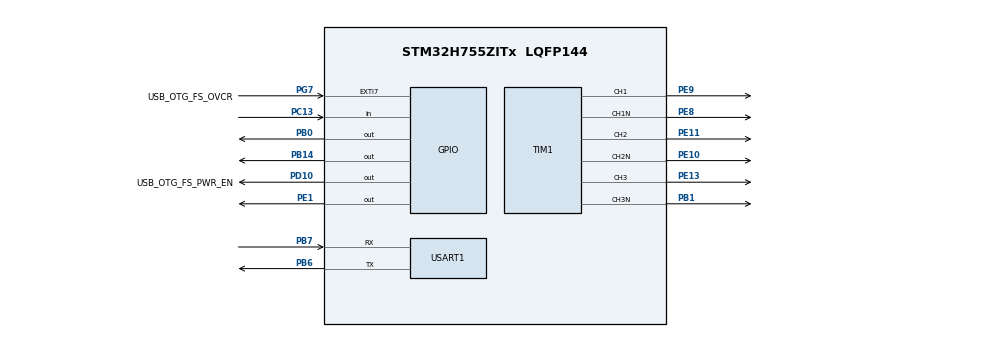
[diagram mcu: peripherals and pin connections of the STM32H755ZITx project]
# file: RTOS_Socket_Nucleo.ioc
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CortexM4.IPs=FATFS_M4\:I,FREERTOS_M4\:I,IWDG2\:I,RCC,WWDG2\:I,DMA,BDMA,MDMA,NVIC2\:I,ETH,USART3,DEBUG,PDM2PCM_M4\:I,PWR,RESMGR_UTILITY,SYS_M4\:I,USB_DEVICE_M4\:I,USB_HOST_M4\:I,CORTEX_M4\:I,GPIO,OPENAMP_M4\:I,VREFBUF,NUCLEO-H755ZI-Q
CortexM7.IPs=FATFS_M7\:I,FREERTOS_M7\:I,IWDG1\:I,RCC\:I,WWDG1\:I,DMA\:I,BDMA\:I,MDMA\:I,NVIC1\:I,ETH\:I,USART3\:I,USB_OTG_FS\:I,SYS\:I,CORTEX_M7\:I,DEBUG\:I,PDM2PCM_M7\:I,PWR\:I,RESMGR_UTILITY\:I,USB_DEVICE_M7\:I,USB_HOST_M7\:I,GPIO\:I,OPENAMP_M7\:I,VREFBUF\:I,NUCLEO-H755ZI-Q\:I,TIM1\:I,USART1\:I,TIM6\:I
Dma.Request0=USART1_TX
Dma.Request1=USART1_RX
Dma.USART1_RX.1.Direction=DMA_PERIPH_TO_MEMORY
Dma.USART1_RX.1.EventEnable=DISABLE
Dma.USART1_RX.1.FIFOMode=DMA_FIFOMODE_DISABLE
Dma.USART1_RX.1.Instance=DMA1_Stream1
Dma.USART1_RX.1.MemDataAlignment=DMA_MDATAALIGN_BYTE
Dma.USART1_RX.1.MemInc=DMA_MINC_ENABLE
Dma.USART1_RX.1.Mode=DMA_CIRCULAR
Dma.USART1_RX.1.PeriphDataAlignment=DMA_PDATAALIGN_BYTE
Dma.USART1_RX.1.PeriphInc=DMA_PINC_DISABLE
Dma.USART1_RX.1.Polarity=HAL_DMAMUX_REQ_GEN_RISING
Dma.USART1_RX.1.Priority=DMA_PRIORITY_LOW
Dma.USART1_RX.1.RequestNumber=1
Dma.USART1_RX.1.SignalID=NONE
Dma.USART1_RX.1.SyncEnable=DISABLE
Dma.USART1_RX.1.SyncPolarity=HAL_DMAMUX_SYNC_NO_EVENT
Dma.USART1_RX.1.SyncRequestNumber=1
Dma.USART1_RX.1.SyncSignalID=NONE
Dma.USART1_TX.0.Direction=DMA_MEMORY_TO_PERIPH
Dma.USART1_TX.0.EventEnable=DISABLE
Dma.USART1_TX.0.FIFOMode=DMA_FIFOMODE_DISABLE
Dma.USART1_TX.0.Instance=DMA1_Stream0
Dma.USART1_TX.0.MemDataAlignment=DMA_MDATAALIGN_BYTE
Dma.USART1_TX.0.MemInc=DMA_MINC_ENABLE
Dma.USART1_TX.0.Mode=DMA_NORMAL
Dma.USART1_TX.0.PeriphDataAlignment=DMA_PDATAALIGN_BYTE
Dma.USART1_TX.0.PeriphInc=DMA_PINC_DISABLE
Dma.USART1_TX.0.Polarity=HAL_DMAMUX_REQ_GEN_RISING
Dma.USART1_TX.0.Priority=DMA_PRIORITY_LOW
Dma.USART1_TX.0.RequestNumber=1
Dma.USART1_TX.0.SignalID=NONE
Dma.USART1_TX.0.SyncEnable=DISABLE
Dma.USART1_TX.0.SyncPolarity=HAL_DMAMUX_SYNC_NO_EVENT
Dma.USART1_TX.0.SyncRequestNumber=1
Dma.USART1_TX.0.SyncSignalID=NONE
FREERTOS_M7.Mutexes01=sl_send_lock,Dynamic,NULL,Available;dl_send_lock,Dynamic,NULL,Available;ph_send_lock,Dynamic,NULL,Available
FREERTOS_M7.Tasks01=defaultTask,24,128,StartDefaultTask,Default,NULL,Dynamic,NULL,NULL;sendTask,8,128,StartSendTask,Default,NULL,Dynamic,NULL,NULL;receiveTask,8,128,StartReceiveTask,Default,NULL,Dynamic,NULL,NULL
FREERTOS_M7.configUSE_NEWLIB_REENTRANT=1
Mcu.Family=STM32H7
Mcu.Name=STM32H755ZITx
Mcu.Package=LQFP144
NUCLEO-H755ZI-Q.BUTTON=1
NUCLEO-H755ZI-Q.LD1=true
NUCLEO-H755ZI-Q.LD2=true
NUCLEO-H755ZI-Q.LD3=true
NUCLEO-H755ZI-Q.VCP=true
NVIC1.DMA1_Stream0_IRQn=true\:5\:0\:false\:false\:true\:true\:false\:true\:true
NVIC1.DMA1_Stream1_IRQn=true\:5\:0\:false\:false\:true\:true\:false\:true\:true
NVIC1.EXTI15_10_IRQn=true\:5\:0\:false\:false\:true\:true\:false\:true\:true
NVIC1.PriorityGroup=NVIC_PRIORITYGROUP_4
NVIC1.TIM6_DAC_IRQn=true\:15\:0\:false\:false\:true\:false\:false\:true\:true
NVIC1.TimeBase=TIM6_DAC_IRQn
NVIC1.TimeBaseIP=TIM6
NVIC2.PriorityGroup=NVIC_PRIORITYGROUP_4
PA1.PinAttribute=CortexM7
PA1.Signal=ETH_REF_CLK
PA11.PinAttribute=CortexM7
PA11.Signal=USB_OTG_FS_DM
PA12.PinAttribute=CortexM7
PA12.Signal=USB_OTG_FS_DP
PA2.PinAttribute=CortexM7
PA2.Signal=ETH_MDIO
PA7.PinAttribute=CortexM7
PA7.Signal=ETH_CRS_DV
PA8.PinAttribute=CortexM7
PA8.Signal=USB_OTG_FS_SOF
PA9.PinAttribute=CortexM7
PA9.Signal=USB_OTG_FS_VBUS
PB0.Signal=GPIO_Output
PB1.Mode=PWM Generation3 CH3 CH3N
PB1.PinAttribute=CortexM7
PB1.Signal=TIM1_CH3N
PB13.PinAttribute=CortexM7
PB13.Signal=ETH_TXD1
PB14.Signal=GPIO_Output
PB6.Mode=Asynchronous
PB6.PinAttribute=CortexM7
PB6.Signal=USART1_TX
PB7.Mode=Asynchronous
PB7.PinAttribute=CortexM7
PB7.Signal=USART1_RX
PC1.PinAttribute=CortexM7
PC1.Signal=ETH_MDC
PC13.Signal=GPIO_Input
PC14-OSC32_IN\ (OSC32_IN).PinAttribute=Free
PC14-OSC32_IN\ (OSC32_IN).Signal=RCC_OSC32_IN
PC15-OSC32_OUT\ (OSC32_OUT).PinAttribute=Free
PC15-OSC32_OUT\ (OSC32_OUT).Signal=RCC_OSC32_OUT
PC4.PinAttribute=CortexM7
PC4.Signal=ETH_RXD0
PC5.PinAttribute=CortexM7
PC5.Signal=ETH_RXD1
PD10.GPIO_Label=USB_OTG_FS_PWR_EN
PD10.PinAttribute=Free
PD10.Signal=GPIO_Output
PD8.Signal=USART3_TX
PD9.Signal=USART3_RX
PE1.Signal=GPIO_Output
PE10.Mode=PWM Generation2 CH2 CH2N
PE10.PinAttribute=CortexM7
PE10.Signal=TIM1_CH2N
PE11.PinAttribute=CortexM7
PE11.Signal=S_TIM1_CH2
PE13.PinAttribute=CortexM7
PE13.Signal=S_TIM1_CH3
PE8.Mode=PWM Generation1 CH1 CH1N
PE8.PinAttribute=CortexM7
PE8.Signal=TIM1_CH1N
PE9.PinAttribute=CortexM7
PE9.Signal=S_TIM1_CH1
PG11.PinAttribute=CortexM7
PG11.Signal=ETH_TX_EN
PG13.PinAttribute=CortexM7
PG13.Signal=ETH_TXD0
PG7.GPIO_Label=USB_OTG_FS_OVCR
PG7.PinAttribute=Free
PG7.Signal=GPXTI7
PH0-OSC_IN\ (PH0).PinAttribute=Free
PH0-OSC_IN\ (PH0).Signal=RCC_OSC_IN
PH1-OSC_OUT\ (PH1).PinAttribute=Free
PH1-OSC_OUT\ (PH1).Signal=RCC_OSC_OUT
ProjectManager.HeapSize=M4-0x200,M7-0x200
ProjectManager.StackSize=M4-0x400,M7-0x400
ProjectManager.TargetToolchain=STM32CubeIDE
RCC.ADCFreq_Value=129000000
RCC.APB1Freq_Value=120000000
RCC.APB2Freq_Value=120000000
RCC.APB3Freq_Value=120000000
RCC.APB4Freq_Value=120000000
RCC.CortexFreq_Value=480000000
RCC.D1PPRE=RCC_APB3_DIV2
RCC.D2PPRE1=RCC_APB1_DIV2
RCC.D2PPRE2=RCC_APB2_DIV2
RCC.D3PPRE=RCC_APB4_DIV2
RCC.DIVM1=4
RCC.DIVN1=60
RCC.DIVQ1=5
RCC.HCLKFreq_Value=240000000
RCC.HPRE=RCC_HCLK_DIV2
RCC.PLL2FRACN=0
RCC.PLL3FRACN=0
RCC.PLLFRACN=0
RCC.SYSCLKFreq_VALUE=480000000
RCC.SYSCLKSource=RCC_SYSCLKSOURCE_PLLCLK
RCC.SupplySource=PWR_LDO_SUPPLY
RCC.USBFreq_Value=192000000
SH.S_TIM1_CH1.0=TIM1_CH1,PWM Generation1 CH1 CH1N
SH.S_TIM1_CH2.0=TIM1_CH2,PWM Generation2 CH2 CH2N
SH.S_TIM1_CH3.0=TIM1_CH3,PWM Generation3 CH3 CH3N
TIM1.Channel-PWM\ Generation1\ CH1\ CH1N=TIM_CHANNEL_1
TIM1.Channel-PWM\ Generation2\ CH2\ CH2N=TIM_CHANNEL_2
TIM1.Channel-PWM\ Generation3\ CH3\ CH3N=TIM_CHANNEL_3
USART1.VirtualMode-Asynchronous=VM_ASYNC
VP_FREERTOS_M7_VS_CMSIS_V2.Mode=CMSIS_V2
VP_NUCLEO-H755ZI-Q_VS_BSP_COMMON.Mode=COMMON
VP_SYS_M4_VS_Systick.Mode=SysTick
VP_SYS_VS_tim6.Mode=TIM6
board=NUCLEO-H755ZI-Q

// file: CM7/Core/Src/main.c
/* USER CODE BEGIN Header */
/**
  ******************************************************************************
  * @file           : main.c
  * @brief          : Main program body
  ******************************************************************************
  * @attention
  *
  * Copyright (c) 2024 STMicroelectronics.
  * All rights reserved.
  *
  * This software is licensed under terms that can be found in the LICENSE file
  * in the root directory of this software component.
  * If no LICENSE file comes with this software, it is provided AS-IS.
  *
  ******************************************************************************
  */
/* USER CODE END Header */
#include "main.h"
#include "cmsis_os.h"

/* USER CODE BEGIN Includes */
#include <string.h>
#include <string.h>
#include <stdlib.h>
#include <stdio.h>

/* USER CODE END Includes */

/* USER CODE BEGIN PD */

#ifndef HSEM_ID_0
#define HSEM_ID_0 (0U) /* HW semaphore 0*/
#endif

#define RX_BUFFER_SIZE 256
#define UART_TIMEOUT 100
#define PACKET_MIN_LENGTH 6
#define SERVER_IP "13.233.25.158"
#define SERVER_PORT 3000
#define SOCKET_INDEX 0

/* USER CODE END PD */

TIM_HandleTypeDef htim1;

UART_HandleTypeDef huart1;
DMA_HandleTypeDef hdma_usart1_rx;
DMA_HandleTypeDef hdma_usart1_tx;

/* Definitions for defaultTask */
osThreadId_t defaultTaskHandle;
const osThreadAttr_t defaultTask_attributes = {
  .name = "defaultTask",
  .stack_size = 128 * 4,
  .priority = (osPriority_t) osPriorityNormal,
};
/* Definitions for sendTask */
osThreadId_t sendTaskHandle;
const osThreadAttr_t sendTask_attributes = {
  .name = "sendTask",
  .stack_size = 128 * 4,
  .priority = (osPriority_t) osPriorityLow,
};
/* Definitions for receiveTask */
osThreadId_t receiveTaskHandle;
const osThreadAttr_t receiveTask_attributes = {
  .name = "receiveTask",
  .stack_size = 128 * 4,
  .priority = (osPriority_t) osPriorityLow,
};
/* Definitions for gpsTask */
osThreadId_t gpsTaskHandle;
const osThreadAttr_t gpsTask_attributes = {
  .name = "gpsTask",
  .stack_size = 128 * 4,
  .priority = (osPriority_t) osPriorityLow,
};
/* Definitions for sl_send_lock */
osMutexId_t sl_send_lockHandle;
const osMutexAttr_t sl_send_lock_attributes = {
  .name = "sl_send_lock"
};
/* Definitions for dl_send_lock */
osMutexId_t dl_send_lockHandle;
const osMutexAttr_t dl_send_lock_attributes = {
  .name = "dl_send_lock"
};
/* Definitions for ph_send_lock */
osMutexId_t ph_send_lockHandle;
const osMutexAttr_t ph_send_lock_attributes = {
  .name = "ph_send_lock"
};
/* Definitions for uart_lock */
osMutexId_t uart_lockHandle;
const osMutexAttr_t uart_lock_attributes = {
  .name = "uart_lock"
};
/* USER CODE BEGIN PV */
char txBuffer[RX_BUFFER_SIZE];        // Buffer for sending AT commands
char rxBuffer[RX_BUFFER_SIZE];        // Buffer for receiving AT responses
char checkBuffer[RX_BUFFER_SIZE];

uint16_t writeIndex = 0;  // Updated by DMA
uint16_t readIndex = 0;   // Updated by application
uint8_t propertyIndex = 0;

typedef enum {
    IMMOBILIZE_STATUS = 0x01,
    RPM_PRESET        = 0x02,
    GPS               = 0x03,
    CURRENT           = 0x04,
    VOLTAGE           = 0x05,
    RPM               = 0x06,
    TEMPERATURE       = 0x07,
    NETWORK_STRENGTH  = 0x08
} ServerPropertyType;

typedef struct {
    uint8_t immobilizeStatus[1]; // 1 byte
    uint8_t rpmPreset[1];        // 1 byte
    uint8_t gpsData[32];          // 6 bytes
    uint8_t currentData[2];      // 2 bytes
    uint8_t voltageData[2];      // 2 bytes
    uint8_t rpm[1];              // 1 byte
    uint8_t temperature[1];      // 1 byte
    uint8_t networkStrength[1];  // 1 byte
} serverProperties;

serverProperties serverAttributes;
/* USER CODE END PV */

void SystemClock_Config(void);
static void MX_GPIO_Init(void);
static void MX_DMA_Init(void);
static void MX_USART1_UART_Init(void);
static void MX_TIM1_Init(void);
void StartDefaultTask(void *argument);
void StartSendTask(void *argument);
void StartReceiveTask(void *argument);
void StartGpsTask(void *argument);

/* USER CODE BEGIN PFP */
void NetworkInit();
void OpenSocket();
void SocketSendData(void);
void SocketReceiveData(void);
void HandleReceivedData(uint8_t writeIndex);
uint8_t encodeServerData(ServerPropertyType type, uint8_t *packet);
void decodeServerData(uint8_t *packet, uint8_t length);
void gps(void);
/* USER CODE END PFP */

int main(void)
{

/* USER CODE BEGIN Boot_Mode_Sequence_0 */
  int32_t timeout;
/* USER CODE END Boot_Mode_Sequence_0 */

/* USER CODE BEGIN Boot_Mode_Sequence_1 */
  /* Wait until CPU2 boots and enters in stop mode or timeout*/
  timeout = 0xFFFF;
  while((__HAL_RCC_GET_FLAG(RCC_FLAG_D2CKRDY) != RESET) && (timeout-- > 0));
  if ( timeout < 0 )
  {
  Error_Handler();
  }
/* USER CODE END Boot_Mode_Sequence_1 */
  /* MCU Configuration--------------------------------------------------------*/

  /* Reset of all peripherals, Initializes the Flash interface and the Systick. */
  HAL_Init();

  /* Configure the system clock */
  SystemClock_Config();
/* USER CODE BEGIN Boot_Mode_Sequence_2 */
/* When system initialization is finished, Cortex-M7 will release Cortex-M4 by means of
HSEM notification */
/*HW semaphore Clock enable*/
__HAL_RCC_HSEM_CLK_ENABLE();
/*Take HSEM */
HAL_HSEM_FastTake(HSEM_ID_0);
/*Release HSEM in order to notify the CPU2(CM4)*/
HAL_HSEM_Release(HSEM_ID_0,0);
/* wait until CPU2 wakes up from stop mode */
timeout = 0xFFFF;
while((__HAL_RCC_GET_FLAG(RCC_FLAG_D2CKRDY) == RESET) && (timeout-- > 0));
if ( timeout < 0 )
{
Error_Handler();
}
/* USER CODE END Boot_Mode_Sequence_2 */

  /* Initialize all configured peripherals */
  MX_GPIO_Init();
  MX_DMA_Init();
  MX_USART1_UART_Init();
  MX_TIM1_Init();
  /* USER CODE BEGIN 2 */
  // Initialize SIM7600
  NetworkInit();

  // Open a socket
  OpenSocket();

  serverAttributes.immobilizeStatus[0] = 0x01;
  serverAttributes.rpmPreset[0] = 0x64;
  memset(serverAttributes.gpsData, 0x00, sizeof(serverAttributes.gpsData));
  serverAttributes.currentData[0] = 0x12;
  serverAttributes.currentData[1] = 0x34;
  serverAttributes.voltageData[0] = 0x56;
  serverAttributes.voltageData[1] = 0x78;
  serverAttributes.rpm[0] = 0x32;
  serverAttributes.temperature[0] = 0x20;
  serverAttributes.networkStrength[0] = 0x05;

  /* USER CODE END 2 */

  /* Init scheduler */
  osKernelInitialize();
  /* Create the mutex(es) */
  /* creation of sl_send_lock */
  sl_send_lockHandle = osMutexNew(&sl_send_lock_attributes);

  /* creation of dl_send_lock */
  dl_send_lockHandle = osMutexNew(&dl_send_lock_attributes);

  /* creation of ph_send_lock */
  ph_send_lockHandle = osMutexNew(&ph_send_lock_attributes);

  /* creation of uart_lock */
  uart_lockHandle = osMutexNew(&uart_lock_attributes);

  /* Create the thread(s) */
  /* creation of defaultTask */
  defaultTaskHandle = osThreadNew(StartDefaultTask, NULL, &defaultTask_attributes);

  /* creation of sendTask */
  sendTaskHandle = osThreadNew(StartSendTask, NULL, &sendTask_attributes);

  /* creation of receiveTask */
  receiveTaskHandle = osThreadNew(StartReceiveTask, NULL, &receiveTask_attributes);

  /* creation of gpsTask */
  gpsTaskHandle = osThreadNew(StartGpsTask, NULL, &gpsTask_attributes);

  /* Initialize leds */
  BSP_LED_Init(LED_GREEN);
  BSP_LED_Init(LED_YELLOW);
  BSP_LED_Init(LED_RED);

  /* Initialize USER push-button, will be used to trigger an interrupt each time it's pressed.*/
  BSP_PB_Init(BUTTON_USER, BUTTON_MODE_EXTI);

  /* Start scheduler */
  osKernelStart();

  /* We should never get here as control is now taken by the scheduler */

  /* Infinite loop */
  while (1)
  {

  }
}

void SystemClock_Config(void)
{
  RCC_OscInitTypeDef RCC_OscInitStruct = {0};
  RCC_ClkInitTypeDef RCC_ClkInitStruct = {0};

  /** Supply configuration update enable
  */
  HAL_PWREx_ConfigSupply(PWR_LDO_SUPPLY);

  /** Configure the main internal regulator output voltage
  */
  __HAL_PWR_VOLTAGESCALING_CONFIG(PWR_REGULATOR_VOLTAGE_SCALE1);

  while(!__HAL_PWR_GET_FLAG(PWR_FLAG_VOSRDY)) {}

  /** Initializes the RCC Oscillators according to the specified parameters
  * in the RCC_OscInitTypeDef structure.
  */
  RCC_OscInitStruct.OscillatorType = RCC_OSCILLATORTYPE_HSI;
  RCC_OscInitStruct.HSIState = RCC_HSI_DIV1;
  RCC_OscInitStruct.HSICalibrationValue = RCC_HSICALIBRATION_DEFAULT;
  RCC_OscInitStruct.PLL.PLLState = RCC_PLL_ON;
  RCC_OscInitStruct.PLL.PLLSource = RCC_PLLSOURCE_HSI;
  RCC_OscInitStruct.PLL.PLLM = 4;
  RCC_OscInitStruct.PLL.PLLN = 50;
  RCC_OscInitStruct.PLL.PLLP = 2;
  RCC_OscInitStruct.PLL.PLLQ = 5;
  RCC_OscInitStruct.PLL.PLLR = 2;
  RCC_OscInitStruct.PLL.PLLRGE = RCC_PLL1VCIRANGE_3;
  RCC_OscInitStruct.PLL.PLLVCOSEL = RCC_PLL1VCOWIDE;
  RCC_OscInitStruct.PLL.PLLFRACN = 0;
  if (HAL_RCC_OscConfig(&RCC_OscInitStruct) != HAL_OK)
  {
    Error_Handler();
  }

  /** Initializes the CPU, AHB and APB buses clocks
  */
  RCC_ClkInitStruct.ClockType = RCC_CLOCKTYPE_HCLK|RCC_CLOCKTYPE_SYSCLK
                              |RCC_CLOCKTYPE_PCLK1|RCC_CLOCKTYPE_PCLK2
                              |RCC_CLOCKTYPE_D3PCLK1|RCC_CLOCKTYPE_D1PCLK1;
  RCC_ClkInitStruct.SYSCLKSource = RCC_SYSCLKSOURCE_PLLCLK;
  RCC_ClkInitStruct.SYSCLKDivider = RCC_SYSCLK_DIV1;
  RCC_ClkInitStruct.AHBCLKDivider = RCC_HCLK_DIV2;
  RCC_ClkInitStruct.APB3CLKDivider = RCC_APB3_DIV2;
  RCC_ClkInitStruct.APB1CLKDivider = RCC_APB1_DIV2;
  RCC_ClkInitStruct.APB2CLKDivider = RCC_APB2_DIV2;
  RCC_ClkInitStruct.APB4CLKDivider = RCC_APB4_DIV2;

  if (HAL_RCC_ClockConfig(&RCC_ClkInitStruct, FLASH_LATENCY_2) != HAL_OK)
  {
    Error_Handler();
  }
}

static void MX_TIM1_Init(void)
{

  TIM_MasterConfigTypeDef sMasterConfig = {0};
  TIM_OC_InitTypeDef sConfigOC = {0};
  TIM_BreakDeadTimeConfigTypeDef sBreakDeadTimeConfig = {0};

  htim1.Instance = TIM1;
  htim1.Init.Prescaler = 0;
  htim1.Init.CounterMode = TIM_COUNTERMODE_CENTERALIGNED1;
  htim1.Init.Period = 65535;
  htim1.Init.ClockDivision = TIM_CLOCKDIVISION_DIV1;
  htim1.Init.RepetitionCounter = 0;
  htim1.Init.AutoReloadPreload = TIM_AUTORELOAD_PRELOAD_DISABLE;
  if (HAL_TIM_PWM_Init(&htim1) != HAL_OK)
  {
    Error_Handler();
  }
  sMasterConfig.MasterOutputTrigger = TIM_TRGO_RESET;
  sMasterConfig.MasterOutputTrigger2 = TIM_TRGO2_RESET;
  sMasterConfig.MasterSlaveMode = TIM_MASTERSLAVEMODE_DISABLE;
  if (HAL_TIMEx_MasterConfigSynchronization(&htim1, &sMasterConfig) != HAL_OK)
  {
    Error_Handler();
  }
  sConfigOC.OCMode = TIM_OCMODE_PWM1;
  sConfigOC.Pulse = 0;
  sConfigOC.OCPolarity = TIM_OCPOLARITY_HIGH;
  sConfigOC.OCNPolarity = TIM_OCNPOLARITY_HIGH;
  sConfigOC.OCFastMode = TIM_OCFAST_DISABLE;
  sConfigOC.OCIdleState = TIM_OCIDLESTATE_RESET;
  sConfigOC.OCNIdleState = TIM_OCNIDLESTATE_RESET;
  if (HAL_TIM_PWM_ConfigChannel(&htim1, &sConfigOC, TIM_CHANNEL_1) != HAL_OK)
  {
    Error_Handler();
  }
  if (HAL_TIM_PWM_ConfigChannel(&htim1, &sConfigOC, TIM_CHANNEL_2) != HAL_OK)
  {
    Error_Handler();
  }
  if (HAL_TIM_PWM_ConfigChannel(&htim1, &sConfigOC, TIM_CHANNEL_3) != HAL_OK)
  {
    Error_Handler();
  }
  sBreakDeadTimeConfig.OffStateRunMode = TIM_OSSR_DISABLE;
  sBreakDeadTimeConfig.OffStateIDLEMode = TIM_OSSI_DISABLE;
  sBreakDeadTimeConfig.LockLevel = TIM_LOCKLEVEL_OFF;
  sBreakDeadTimeConfig.DeadTime = 0;
  sBreakDeadTimeConfig.BreakState = TIM_BREAK_DISABLE;
  sBreakDeadTimeConfig.BreakPolarity = TIM_BREAKPOLARITY_HIGH;
  sBreakDeadTimeConfig.BreakFilter = 0;
  sBreakDeadTimeConfig.Break2State = TIM_BREAK2_DISABLE;
  sBreakDeadTimeConfig.Break2Polarity = TIM_BREAK2POLARITY_HIGH;
  sBreakDeadTimeConfig.Break2Filter = 0;
  sBreakDeadTimeConfig.AutomaticOutput = TIM_AUTOMATICOUTPUT_DISABLE;
  if (HAL_TIMEx_ConfigBreakDeadTime(&htim1, &sBreakDeadTimeConfig) != HAL_OK)
  {
    Error_Handler();
  }
  HAL_TIM_MspPostInit(&htim1);

}

static void MX_USART1_UART_Init(void)
{

  huart1.Instance = USART1;
  huart1.Init.BaudRate = 115200;
  huart1.Init.WordLength = UART_WORDLENGTH_8B;
  huart1.Init.StopBits = UART_STOPBITS_1;
  huart1.Init.Parity = UART_PARITY_NONE;
  huart1.Init.Mode = UART_MODE_TX_RX;
  huart1.Init.HwFlowCtl = UART_HWCONTROL_NONE;
  huart1.Init.OverSampling = UART_OVERSAMPLING_16;
  huart1.Init.OneBitSampling = UART_ONE_BIT_SAMPLE_DISABLE;
  huart1.Init.ClockPrescaler = UART_PRESCALER_DIV1;
  huart1.AdvancedInit.AdvFeatureInit = UART_ADVFEATURE_NO_INIT;
  if (HAL_UART_Init(&huart1) != HAL_OK)
  {
    Error_Handler();
  }
  if (HAL_UARTEx_SetTxFifoThreshold(&huart1, UART_TXFIFO_THRESHOLD_1_8) != HAL_OK)
  {
    Error_Handler();
  }
  if (HAL_UARTEx_SetRxFifoThreshold(&huart1, UART_RXFIFO_THRESHOLD_1_8) != HAL_OK)
  {
    Error_Handler();
  }
  if (HAL_UARTEx_DisableFifoMode(&huart1) != HAL_OK)
  {
    Error_Handler();
  }

}

static void MX_DMA_Init(void)
{

  /* DMA controller clock enable */
  __HAL_RCC_DMA1_CLK_ENABLE();

  /* DMA interrupt init */
  /* DMA1_Stream0_IRQn interrupt configuration */
  HAL_NVIC_SetPriority(DMA1_Stream0_IRQn, 5, 0);
  HAL_NVIC_EnableIRQ(DMA1_Stream0_IRQn);
  /* DMA1_Stream1_IRQn interrupt configuration */
  HAL_NVIC_SetPriority(DMA1_Stream1_IRQn, 5, 0);
  HAL_NVIC_EnableIRQ(DMA1_Stream1_IRQn);

}

static void MX_GPIO_Init(void)
{
  GPIO_InitTypeDef GPIO_InitStruct = {0};

  /* GPIO Ports Clock Enable */
  __HAL_RCC_GPIOC_CLK_ENABLE();
  __HAL_RCC_GPIOA_CLK_ENABLE();
  __HAL_RCC_GPIOE_CLK_ENABLE();
  __HAL_RCC_GPIOB_CLK_ENABLE();
  __HAL_RCC_GPIOD_CLK_ENABLE();
  __HAL_RCC_GPIOG_CLK_ENABLE();

  /*Configure GPIO pins : PC1 PC4 PC5 */
  GPIO_InitStruct.Pin = GPIO_PIN_1|GPIO_PIN_4|GPIO_PIN_5;
  GPIO_InitStruct.Mode = GPIO_MODE_AF_PP;
  GPIO_InitStruct.Pull = GPIO_NOPULL;
  GPIO_InitStruct.Speed = GPIO_SPEED_FREQ_LOW;
  GPIO_InitStruct.Alternate = GPIO_AF11_ETH;
  HAL_GPIO_Init(GPIOC, &GPIO_InitStruct);

  /*Configure GPIO pins : PA1 PA2 PA7 */
  GPIO_InitStruct.Pin = GPIO_PIN_1|GPIO_PIN_2|GPIO_PIN_7;
  GPIO_InitStruct.Mode = GPIO_MODE_AF_PP;
  GPIO_InitStruct.Pull = GPIO_NOPULL;
  GPIO_InitStruct.Speed = GPIO_SPEED_FREQ_LOW;
  GPIO_InitStruct.Alternate = GPIO_AF11_ETH;
  HAL_GPIO_Init(GPIOA, &GPIO_InitStruct);

  /*Configure GPIO pin : PB13 */
  GPIO_InitStruct.Pin = GPIO_PIN_13;
  GPIO_InitStruct.Mode = GPIO_MODE_AF_PP;
  GPIO_InitStruct.Pull = GPIO_NOPULL;
  GPIO_InitStruct.Speed = GPIO_SPEED_FREQ_LOW;
  GPIO_InitStruct.Alternate = GPIO_AF11_ETH;
  HAL_GPIO_Init(GPIOB, &GPIO_InitStruct);

  /*Configure GPIO pins : PD8 PD9 */
  GPIO_InitStruct.Pin = GPIO_PIN_8|GPIO_PIN_9;
  GPIO_InitStruct.Mode = GPIO_MODE_AF_PP;
  GPIO_InitStruct.Pull = GPIO_NOPULL;
  GPIO_InitStruct.Speed = GPIO_SPEED_FREQ_LOW;
  GPIO_InitStruct.Alternate = GPIO_AF7_USART3;
  HAL_GPIO_Init(GPIOD, &GPIO_InitStruct);

  /*Configure GPIO pins : PA8 PA11 PA12 */
  GPIO_InitStruct.Pin = GPIO_PIN_8|GPIO_PIN_11|GPIO_PIN_12;
  GPIO_InitStruct.Mode = GPIO_MODE_AF_PP;
  GPIO_InitStruct.Pull = GPIO_NOPULL;
  GPIO_InitStruct.Speed = GPIO_SPEED_FREQ_LOW;
  GPIO_InitStruct.Alternate = GPIO_AF10_OTG1_FS;
  HAL_GPIO_Init(GPIOA, &GPIO_InitStruct);

  /*Configure GPIO pins : PG11 PG13 */
  GPIO_InitStruct.Pin = GPIO_PIN_11|GPIO_PIN_13;
  GPIO_InitStruct.Mode = GPIO_MODE_AF_PP;
  GPIO_InitStruct.Pull = GPIO_NOPULL;
  GPIO_InitStruct.Speed = GPIO_SPEED_FREQ_LOW;
  GPIO_InitStruct.Alternate = GPIO_AF11_ETH;
  HAL_GPIO_Init(GPIOG, &GPIO_InitStruct);

}

/* USER CODE BEGIN 4 */

void NetworkInit() {

	strcpy(txBuffer, "ATE0\r\n");
	HAL_UART_Transmit(&huart1, (uint8_t *)txBuffer, strlen(txBuffer), UART_TIMEOUT);
	memset(txBuffer, '\0' , sizeof(txBuffer));

	memset(rxBuffer, '\0' , sizeof(rxBuffer));
	HAL_UART_Receive(&huart1, (uint8_t *)rxBuffer, sizeof(rxBuffer), UART_TIMEOUT);
	//HAL_UART_Receive_DMA(&huart1, (uint8_t *)rxBuffer, 256);

    // Check SIM is ready
    strcpy(txBuffer, "AT+CPIN?\r\n");
    HAL_UART_Transmit(&huart1, (uint8_t *)txBuffer, strlen(txBuffer), UART_TIMEOUT);
    memset(txBuffer, '\0' , sizeof(txBuffer));

    memset(rxBuffer, '\0' , sizeof(rxBuffer));
    HAL_UART_Receive(&huart1, (uint8_t *)rxBuffer, sizeof(rxBuffer), UART_TIMEOUT);
    //HAL_UART_Receive_DMA(&huart1, (uint8_t *)rxBuffer, 256);

    // Check network registration
    strcpy(txBuffer, "AT+CREG=2\r\n");
    HAL_UART_Transmit(&huart1, (uint8_t *)txBuffer, strlen(txBuffer), UART_TIMEOUT);
    memset(txBuffer, '\0' , sizeof(txBuffer));

    memset(rxBuffer, '\0' , sizeof(rxBuffer));
    HAL_UART_Receive(&huart1, (uint8_t *)rxBuffer, sizeof(rxBuffer), UART_TIMEOUT);
    //HAL_UART_Receive_DMA(&huart1, (uint8_t *)rxBuffer, 256);

    // PDP Contextn
	strcpy(txBuffer, "AT+CGACT=1,1\r\n");
	HAL_UART_Transmit(&huart1, (uint8_t *)txBuffer, strlen(txBuffer), UART_TIMEOUT);
	memset(txBuffer, '\0' , sizeof(txBuffer));

	memset(rxBuffer, '\0' , sizeof(rxBuffer));
	HAL_UART_Receive(&huart1, (uint8_t *)rxBuffer, sizeof(rxBuffer), UART_TIMEOUT);

    // Set APN
    strcpy(txBuffer, "AT+CGDCONT=1,\"IP\",\"airtelgprs.com\"\r\n");
    HAL_UART_Transmit(&huart1, (uint8_t *)txBuffer, strlen(txBuffer), UART_TIMEOUT);
    memset(txBuffer, '\0' , sizeof(txBuffer));

    memset(rxBuffer, '\0' , sizeof(rxBuffer));
    HAL_UART_Receive(&huart1, (uint8_t *)rxBuffer, sizeof(rxBuffer), UART_TIMEOUT);
    //HAL_UART_Receive_DMA(&huart1, (uint8_t *)rxBuffer, 256);

    // Set GPS Mode
	strcpy(txBuffer, "AT+CGPS=1\r\n");
	HAL_UART_Transmit(&huart1, (uint8_t *)txBuffer, strlen(txBuffer), UART_TIMEOUT);
	memset(txBuffer, '\0' , sizeof(txBuffer));

	memset(rxBuffer, '\0' , sizeof(rxBuffer));
	HAL_UART_Receive(&huart1, (uint8_t *)rxBuffer, sizeof(rxBuffer), UART_TIMEOUT);
	//HAL_UART_Receive_DMA(&huart1, (uint8_t *)rxBuffer, 256);

    // Start TCP/IP service
    strcpy(txBuffer, "AT+NETOPEN\r\n");
    HAL_UART_Transmit(&huart1, (uint8_t *)txBuffer, strlen(txBuffer), UART_TIMEOUT);
    memset(txBuffer, '\0' , sizeof(txBuffer));

    memset(rxBuffer, '\0' , sizeof(rxBuffer));
    HAL_UART_Receive(&huart1, (uint8_t *)rxBuffer, sizeof(rxBuffer), UART_TIMEOUT);
    //HAL_UART_Receive_DMA(&huart1, (uint8_t *)rxBuffer, 256);

    // Check response
    if (strstr(rxBuffer, "+NETOPEN: 0") == NULL) {
        //Error_Handler();
    }
}

void OpenSocket() {
    sprintf(txBuffer, "AT+CIPOPEN=%d,\"TCP\",\"%s\",%d\r\n", SOCKET_INDEX, SERVER_IP, SERVER_PORT);
    HAL_UART_Transmit(&huart1, (uint8_t *)txBuffer, strlen(txBuffer), UART_TIMEOUT);
    memset(txBuffer, '\0' , sizeof(txBuffer));

    memset(rxBuffer, '\0' , sizeof(rxBuffer));
    HAL_UART_Receive(&huart1, (uint8_t *)rxBuffer, sizeof(rxBuffer), UART_TIMEOUT);
    //HAL_UART_Receive_DMA(&huart1, (uint8_t *)rxBuffer, 256);
    memset(rxBuffer, '\0' , sizeof(rxBuffer));

    //memset(txBuffer, '\0' , sizeof(txBuffer));
    // Check response
    if (strstr(rxBuffer, "+CIPOPEN: 0,0") == NULL) {
        //Error_Handler();
    }
    HAL_UARTEx_ReceiveToIdle_DMA(&huart1, (uint8_t *)rxBuffer, RX_BUFFER_SIZE);

    // Enable UART IDLE line detection interrupt
    //__HAL_UART_ENABLE_IT(&huart1, UART_IT_IDLE);
}

void SocketSendData(void) {
	uint8_t data[40];

	encodeServerData(propertyIndex, data);

	osMutexAcquire(uart_lockHandle, osWaitForever);

	sprintf(txBuffer, "AT+CIPSEND=%d,%d\r\n", SOCKET_INDEX, sizeof(data));

    // Wait for `>` prompt
    while (!strstr((char *)checkBuffer, ">")) {

    	HAL_UART_Transmit(&huart1, (uint8_t *)txBuffer, strlen(txBuffer), UART_TIMEOUT);
    	osDelay(10);  // Wait for the response
    }
    memset(txBuffer, '\0' , sizeof(txBuffer));

    // Send data
    HAL_UART_Transmit(&huart1, (uint8_t *)data, sizeof(data), UART_TIMEOUT);
    memset(txBuffer, '\0' , sizeof(txBuffer));

    osMutexRelease(uart_lockHandle);

    if (strstr(rxBuffer, "SEND OK") == NULL) {
        //Error_Handler();
    }
    if(++propertyIndex > 8)	propertyIndex  = 0;
}

void SocketReceiveData(void) {
	int length = sizeof(rxBuffer);

	osMutexAcquire(uart_lockHandle, osWaitForever);

    sprintf(txBuffer, "AT+CIPRXGET=3,%d,%d\r\n", SOCKET_INDEX, length);

    HAL_UART_Transmit(&huart1, (uint8_t *)txBuffer, strlen(txBuffer), UART_TIMEOUT);
    memset(txBuffer, '\0' , sizeof(txBuffer));

    osMutexRelease(uart_lockHandle);

    // Check if data received successfully
    if (strstr(rxBuffer, "+CIPRXGET:") == NULL) {
        //Error_Handler();
    }
}

void gps(void) {
	char *gpsString;
	osMutexAcquire(uart_lockHandle, osWaitForever);

	strcpy(txBuffer, "AT+CGPSINFO\r\n");

	while (!strstr((char *)checkBuffer, "+CGPSINFO:")) {

	HAL_UART_Transmit(&huart1, (uint8_t *)txBuffer, strlen(txBuffer), UART_TIMEOUT);
	osDelay(10);  // Wait for the response
	}

	gpsString = strstr((char *)checkBuffer, "+CGPSINFO:");

	memset(txBuffer, '\0' , sizeof(txBuffer));

	// Move pointer past "+CGPSINFO:"
	gpsString += 10;

	// Example response: 3113.343286,N,12121.234064,E,...
	char latitude[16] = {0};
	char longitude[16] = {0};

	// Extract latitude and longitude strings
	char *token = strtok(gpsString, ",");
	if (token != NULL) strncpy(latitude, token, sizeof(latitude) - 1);
	token = strtok(NULL, ","); // Skip N/S indicator
	token = strtok(NULL, ",");
	if (token != NULL) strncpy(longitude, token, sizeof(longitude) - 1);

	// Format and store in gpsData
	sprintf((char *)serverAttributes.gpsData, "%s,%s", latitude, longitude);

	osMutexRelease(uart_lockHandle);
}

void HandleReceivedData(uint8_t writeIndex) {

	uint16_t newDataCount = (writeIndex >= readIndex)
	                            ? (writeIndex - readIndex)
	                            : (RX_BUFFER_SIZE - readIndex + writeIndex);
	memset(checkBuffer, '\0', RX_BUFFER_SIZE);
	for (uint16_t i = 0; i < newDataCount; i++) {
		// Copy new data to the process buffer
		uint8_t newByte = rxBuffer[readIndex];
		checkBuffer[i] = newByte;

		// Increment read index circularly
		readIndex = (readIndex + 1) % RX_BUFFER_SIZE;
	}
	// Check if we have a complete packet
	if (readIndex >= PACKET_MIN_LENGTH) { // Assume minimum length is 2 bytes (Type + Length)
		if (checkBuffer[0] == 0xAA) {
			decodeServerData((uint8_t *)checkBuffer, readIndex);
		}
	}
}

uint8_t encodeServerData(ServerPropertyType type, uint8_t *packet) {
    uint8_t payloadLength = 0;
    uint8_t *payload;

    switch (type) {
        case IMMOBILIZE_STATUS:
            payload = serverAttributes.immobilizeStatus;
            payloadLength = sizeof(serverAttributes.immobilizeStatus);
            break;
        case RPM_PRESET:
            payload = serverAttributes.rpmPreset;
            payloadLength = sizeof(serverAttributes.rpmPreset);
            break;
        case GPS:
            payload = serverAttributes.gpsData;
            payloadLength = sizeof(serverAttributes.gpsData);
            break;
        case CURRENT:
            payload = serverAttributes.currentData;
            payloadLength = sizeof(serverAttributes.currentData);
            break;
        case VOLTAGE:
            payload = serverAttributes.voltageData;
            payloadLength = sizeof(serverAttributes.voltageData);
            break;
        case RPM:
            payload = serverAttributes.rpm;
            payloadLength = sizeof(serverAttributes.rpm);
            break;
        case TEMPERATURE:
            payload = serverAttributes.temperature;
            payloadLength = sizeof(serverAttributes.temperature);
            break;
        case NETWORK_STRENGTH:
            payload = serverAttributes.networkStrength;
            payloadLength = sizeof(serverAttributes.networkStrength);
            break;
        default:
            return 0; // Unknown type
    }

    // Create the packet
    uint8_t index = 0;
    packet[index++] = 0xAA;  // Header byte 1
    packet[index++] = 0xBB;  // Header byte 2
    packet[index++] = type;  // Property type
    packet[index++] = payloadLength; // Payload length

    // Copy payload
    memcpy(&packet[index], payload, payloadLength);
    index += payloadLength;

    // Add checksum
    uint8_t checksum = 0;
    for (uint8_t i = 2; i < index; i++) {
        checksum ^= packet[i];
    }
    packet[index++] = checksum;

    return index; // Total packet length
}

void decodeServerData(uint8_t *packet, uint8_t length) {
    if (length < 5) return; // Invalid packet length

    // Validate header
    if (packet[0] != 0xAA || packet[1] != 0xBB) return;

    // Extract type and payload length
    ServerPropertyType type = packet[2];
    uint8_t payloadLength = packet[3];

    // Validate checksum
   // uint8_t checksum = 0;
   // for (uint8_t i = 2; i < 4 + payloadLength; i++) {
   //     checksum ^= packet[i];
   // }
   // if (checksum != packet[4 + payloadLength]) return;

    // Extract payload
    uint8_t *payload = &packet[4];

    // Update serverAttributes
    switch (type) {
        case IMMOBILIZE_STATUS:
            memcpy(serverAttributes.immobilizeStatus, payload, payloadLength);
            break;
        case RPM_PRESET:
            memcpy(serverAttributes.rpmPreset, payload, payloadLength);
            break;
        case GPS:
            memcpy(serverAttributes.gpsData, payload, payloadLength);
            break;
        case CURRENT:
            memcpy(serverAttributes.currentData, payload, payloadLength);
            break;
        case VOLTAGE:
            memcpy(serverAttributes.voltageData, payload, payloadLength);
            break;
        case RPM:
            memcpy(serverAttributes.rpm, payload, payloadLength);
            break;
        case TEMPERATURE:
            memcpy(serverAttributes.temperature, payload, payloadLength);
            break;
        case NETWORK_STRENGTH:
            memcpy(serverAttributes.networkStrength, payload, payloadLength);
            break;
        default:
            // Unknown type
            break;
    }
}

void HAL_UARTEx_RxEventCallback(UART_HandleTypeDef *huart, uint16_t Size) {
    //if (__HAL_UART_GET_FLAG(&huart1, UART_FLAG_IDLE)) {
      //  __HAL_UART_CLEAR_IDLEFLAG(&huart1);  // Clear the idle flag

	// Process received data
	writeIndex = Size;//(RX_BUFFER_SIZE - __HAL_DMA_GET_COUNTER(huart->hdmarx));// % RX_BUFFER_SIZE;
	HandleReceivedData(writeIndex);
}

/* USER CODE END 4 */

void StartDefaultTask(void *argument)
{
  for(;;)
  {
    osDelay(1);
  }
}

void StartSendTask(void *argument)
{
  /* USER CODE BEGIN StartSendTask */
  /* Infinite loop */
  for(;;)
  {
	  SocketSendData();
	  osDelay(20);
  }
  /* USER CODE END StartSendTask */
}

void StartReceiveTask(void *argument)
{
  /* USER CODE BEGIN StartReceiveTask */
  /* Infinite loop */
  for(;;)
  {
	  SocketReceiveData();
	  osDelay(20);
  }
  /* USER CODE END StartReceiveTask */
}

void StartGpsTask(void *argument)
{
  /* USER CODE BEGIN StartGpsTask */
  /* Infinite loop */
  for(;;)
  {
	gps();
    osDelay(20);
  }
  /* USER CODE END StartGpsTask */
}

void HAL_TIM_PeriodElapsedCallback(TIM_HandleTypeDef *htim)
{
  if (htim->Instance == TIM6) {
    HAL_IncTick();
  }
}

void Error_Handler(void)
{
  __disable_irq();
  while (1)
  {
  }
}
